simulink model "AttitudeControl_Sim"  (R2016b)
settings: Solver=ode4  StartTime=0.0  StopTime=30  FixedStep=0.001  RelTol=1e-3
InitFcn:
  | Init_control;
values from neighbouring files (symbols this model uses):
  DEG2RAD = 0.0174533    [Init_control.m]
  Kd_PITCH_AgngleRate = 0.001    [Init_control.m]
  Kd_ROLL_AgngleRate = 0.001    [Init_control.m]
  Kd_YAW_AngleRate = 0.00    (= 0)    [Init_control.m]
  Ki_PITCH_AgngleRate = 0.02    [Init_control.m]
  Ki_ROLL_AgngleRate = 0.02    [Init_control.m]
  Ki_YAW_AngleRate = 0.01    [Init_control.m]
  Kp_PITCH_AgngleRate = 0.1    [Init_control.m]
  Kp_PITCH_ANGLE = 6.5    [Init_control.m]
  Kp_ROLL_AgngleRate = 0.1    [Init_control.m]
  Kp_ROLL_ANGLE = 6.5    [Init_control.m]
  Kp_YAW_AngleRate = 0.3    [Init_control.m]
  MAX_CONTROL_ANGLE_PITCH = 35    [Init_control.m]
  MAX_CONTROL_ANGLE_RATE_PITCH = 220    [Init_control.m]
  MAX_CONTROL_ANGLE_RATE_ROLL = 220    [Init_control.m]
  MAX_CONTROL_ANGLE_RATE_Y = 200    [Init_control.m]
  MAX_CONTROL_ANGLE_ROLL = 35    [Init_control.m]
  Saturation_I_RP_Max = 0.3    [Init_control.m]
  Saturation_I_RP_Min = -0.3    [Init_control.m]
  Saturation_I_Y_Max = 0.2    [Init_control.m]
  Saturation_I_Y_Min = -0.2    [Init_control.m]
  THR_HOVER = 0.609    [Init_control.m]
undefined symbols (not defined in the file or in its folder): DiscIntNeverNeededParam, earthRadius, Receive, Send
libraries: simulink x5, aerolibfltsims x3, aerolib6dof2 x1
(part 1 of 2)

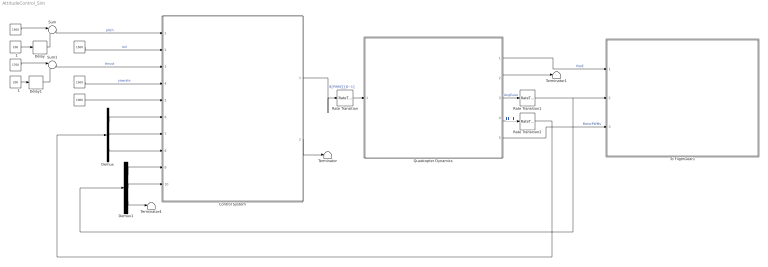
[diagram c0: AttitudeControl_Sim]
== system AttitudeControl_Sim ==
  " " : Constant  Value=1000  OutDataTypeStr=uint16
  "  " : Constant  Value=1500  OutDataTypeStr=uint16
  "   " : Constant  Value=1500  OutDataTypeStr=uint16
  "      " : Constant  Value=1700  OutDataTypeStr=uint16
  "          " : Constant  Value=1500  OutDataTypeStr=uint16
  "      1" : Constant  Value=200  OutDataTypeStr=uint16
  "  1" : Constant  Value=100  OutDataTypeStr=uint16
  Control System : Subsystem
  Delay : Delay  DelayLength=3000  InitialCondition=0  SampleTime=0.001
  Delay1 : Delay  DelayLength=1000  InitialCondition=0  SampleTime=0.001
  Demux : Demux  Outputs=3
  Demux1 : Demux  Outputs=3
  Quadcopter Dynamics : Subsystem
  Rate Transition : RateTransition  OutPortSampleTime=sampleRate
  Rate Transition1 : RateTransition  OutPortSampleTime=sampleRate
  Rate Transition2 : RateTransition  OutPortSampleTime=sampleRate
  Sum : Sum  Inputs=|++
  Sum1 : Sum  Inputs=|+-
  Terminator : Terminator
  Terminator1 : Terminator
  Terminator4 : Terminator
  To FlightGear1 : Subsystem
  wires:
  Quadcopter Dynamics/1(PosE) -> To FlightGear1/1(PosE)  "PosE"
  Quadcopter Dynamics/5(MotorRPMS) -> To FlightGear1/3(MotorPWMs)  "MotorPWMs"
  Control System/2(LED) -> Terminator/1
  Quadcopter Dynamics/3(AngEuler) -> Rate Transition1/1  "AngEular"
  Quadcopter Dynamics/4(AngRateB) -> Rate Transition2/1  "转动角速度"
  Demux/1 -> Control System/6(p)
  Demux/2 -> Control System/7(q)
  Demux/3 -> Control System/8(r)
  Demux1/1 -> Control System/9(roll)
  Demux1/2 -> Control System/10(pitch)
  Demux1/3 -> Terminator4/1
  "  "/1 -> Sum/1
  "  1"/1 -> Delay/1
  Delay/1 -> Sum/2
  Control System/1(PWM) -> Rate Transition/1  "8维PWM信号（0~1）"
  Quadcopter Dynamics/2(VelE) -> Terminator1/1
  Rate Transition/1 -> Quadcopter Dynamics/1(inPWMs)
  Rate Transition1/1 -> Demux1/1, To FlightGear1/2(AngEular)
  Rate Transition2/1 -> Demux/1
  "      "/1 -> Sum1/1
  "      1"/1 -> Delay1/1
  Delay1/1 -> Sum1/2
  Sum/1 -> Control System/1(ch1)  "pitch"
  "   "/1 -> Control System/2(ch2)  "roll"
  Sum1/1 -> Control System/3(ch3)  "thrust"
  "          "/1 -> Control System/4(ch4)  "yawrate"
  " "/1 -> Control System/5(ch5)

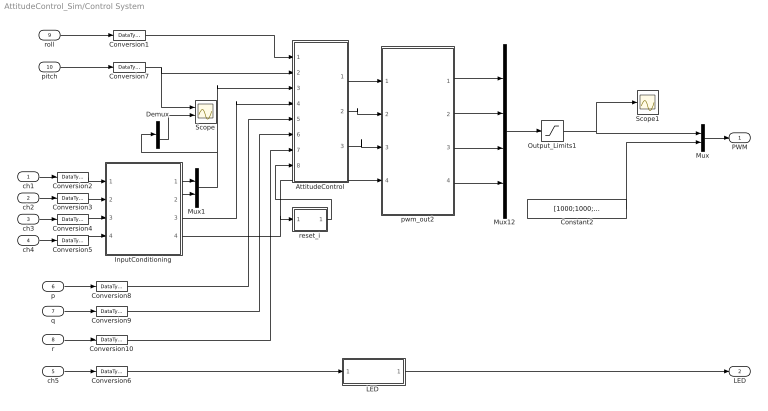
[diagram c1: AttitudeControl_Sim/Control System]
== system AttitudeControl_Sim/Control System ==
  ch1 : Inport  OutDataTypeStr=uint16  PortDimensions=1
  ch2 : Inport  Port=2  OutDataTypeStr=uint16  PortDimensions=1
  ch3 : Inport  Port=3  OutDataTypeStr=uint16  PortDimensions=1
  ch4 : Inport  Port=4  OutDataTypeStr=uint16  PortDimensions=1
  ch5 : Inport  Port=5  OutDataTypeStr=uint16  PortDimensions=1  Interpolate=off
  p : Inport  Port=6  PortDimensions=1
  q : Inport  Port=7  PortDimensions=1
  r : Inport  Port=8  PortDimensions=1
  roll : Inport  Port=9  PortDimensions=1
  pitch : Inport  Port=10  PortDimensions=1
  AttitudeControl : Subsystem
  Constant2 : Constant  Value=[1000;1000;1000;1000]
  Conversion{1..10} (10 alike) : DataTypeConversion  OutDataTypeStr=double
  Demux : Demux  Outputs=2
  InputConditioning : Subsystem
  "LED " : Subsystem
  Mux : Mux  Inputs=2
  Mux1 : Mux  Inputs=2
  Mux12 : Mux
  Output_Limits1 : Saturate  UpperLimit=2000  LowerLimit=1000
  Scope : Scope  NumInputPorts=2
  Scope1 : Scope
  pwm_out2 : MATLAB Function  SystemSampleTime=0.004
  reset_i : Subsystem
  PWM : Outport  PortDimensions=8
  LED : Outport  Port=2  PortDimensions=1
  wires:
  Mux12/1 -> Output_Limits1/1
  AttitudeControl/2(torque_pitch) -> pwm_out2/2(Pitch)
  AttitudeControl/1(torque_roll) -> pwm_out2/1(Roll)
  ch3/1 -> Conversion4/1
  pwm_out2/1(M1) -> Mux12/1
  ch5/1 -> Conversion6/1
  pwm_out2/3(M3) -> Mux12/3
  pwm_out2/2(M2) -> Mux12/2
  r/1 -> Conversion10/1
  AttitudeControl/3(torque_yaw) -> pwm_out2/3(Yaw)
  Mux1/1 -> AttitudeControl/3(roll_pitch_d), Demux/1
  q/1 -> Conversion9/1
  InputConditioning/3(yawRate_d) -> AttitudeControl/4(yawRate_d)
  p/1 -> Conversion8/1
  ch4/1 -> Conversion5/1
  pwm_out2/4(M4) -> Mux12/4
  "LED "/1(Out1) -> LED/1
  Conversion6/1 -> "LED "/1(In1)
  Conversion5/1 -> InputConditioning/4(ch4)
  Conversion4/1 -> InputConditioning/3(ch3)
  pitch/1 -> Conversion7/1
  Demux/2 -> Scope/2
  roll/1 -> Conversion1/1
  Constant2/1 -> Mux/2
  Output_Limits1/1 -> Scope1/1, Mux/1
  Mux/1 -> PWM/1
  ch1/1 -> Conversion2/1
  ch2/1 -> Conversion3/1
  Conversion2/1 -> InputConditioning/1(ch1)
  Conversion3/1 -> InputConditioning/2(ch2)
  InputConditioning/1(Roll_d) -> Mux1/1
  InputConditioning/2(Pitch_d) -> Mux1/2
  Conversion1/1 -> AttitudeControl/1(phi)
  Conversion7/1 -> AttitudeControl/2(theta), Scope/1
  Conversion8/1 -> AttitudeControl/5(p)
  Conversion9/1 -> AttitudeControl/6(q)
  Conversion10/1 -> AttitudeControl/7(r)
  reset_i/1(Out1) -> AttitudeControl/8(reset_i)
  InputConditioning/4(Thrust) -> pwm_out2/4(Thrust), reset_i/1(In1)

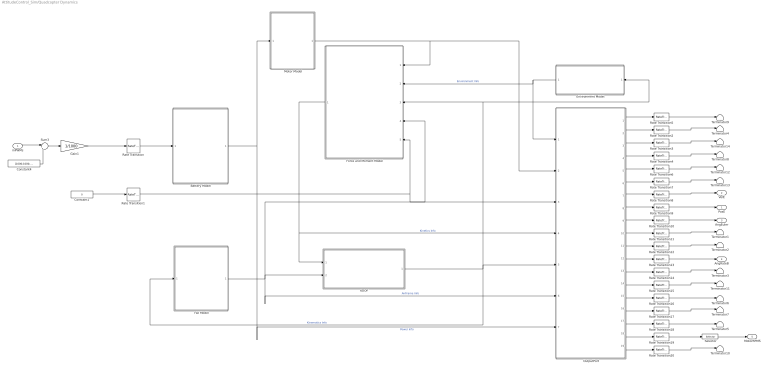
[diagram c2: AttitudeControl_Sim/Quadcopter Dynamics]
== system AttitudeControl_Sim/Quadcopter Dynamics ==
  inPWMs : Inport  PortDimensions=8
  6DOF : Subsystem
  Battery Model : Subsystem
  Constant1 : Constant  Value=0
  Constant4 : Constant  Value=[1000;1000;1000;1000;1000;1000;1000;1000]
  Environment Model : Subsystem
  Fail Model : Subsystem
  Force and Moment Model : Subsystem
  Gain1 : Gain  Gain=1/1000
  Motor Model : Subsystem
  OutputPort : Subsystem
  Rate Transition{,1..20} (21 alike) : RateTransition  OutPortSampleTime=ModelParam_BusSampleRate
  Selector : Selector  InputPortWidth=8  IndexOptions=Index vector (dialog)  Indices=[1 2 3 4]  OutputSizes=1
  Sum3 : Sum  Inputs=|+-
  Terminator{1..14} (14 alike) : Terminator
  PosE : Outport
  VelE : Outport  Port=2
  AngEuler : Outport  Port=3
  AngRateB : Outport  Port=4
  MotorRPMS : Outport  Port=5
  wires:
  Selector/1 -> MotorRPMS/1
  Constant4/1 -> Sum3/2
  inPWMs/1 -> Sum3/1
  Constant1/1 -> Rate Transition1/1
  Sum3/1 -> Gain1/1
  Rate Transition5/1 -> Terminator9/1
  Rate Transition2/1 -> Terminator4/1
  Rate Transition3/1 -> Terminator14/1
  Rate Transition4/1 -> Terminator8/1
  Rate Transition6/1 -> Terminator12/1
  Rate Transition7/1 -> Terminator13/1
  Rate Transition8/1 -> VelE/1
  Rate Transition9/1 -> PosE/1
  Rate Transition10/1 -> AngEuler/1
  Rate Transition11/1 -> Terminator1/1
  Rate Transition12/1 -> Terminator2/1
  Rate Transition13/1 -> AngRateB/1
  Rate Transition14/1 -> Terminator3/1
  Rate Transition15/1 -> Terminator11/1
  Rate Transition16/1 -> Terminator6/1
  Rate Transition17/1 -> Terminator7/1
  Rate Transition18/1 -> Terminator5/1
  Rate Transition19/1 -> Selector/1
  Rate Transition20/1 -> Terminator10/1
  Gain1/1 -> Rate Transition/1
  OutputPort/2(MavLinkStateQuatData) -> Rate Transition2/1
  Motor Model/1(MotorRads) -> OutputPort/2(MotorRads), Force and Moment Model/1(MotorRads)
  OutputPort/15(landed) -> Rate Transition16/1
  OutputPort/3(MavLinkGPSData) -> Rate Transition3/1
  OutputPort/1(MavLinkSensorData) -> Rate Transition5/1
  OutputPort/14(FailInfo) -> Rate Transition15/1
  OutputPort/13(AccB) -> Rate Transition14/1
  OutputPort/12(RateB) -> Rate Transition13/1
  OutputPort/11(PosGPS) -> Rate Transition12/1
  OutputPort/10(AngQuatern) -> Rate Transition11/1
  OutputPort/9(AngEuler) -> Rate Transition10/1
  OutputPort/8(PosE) -> Rate Transition9/1
  OutputPort/7(VelE) -> Rate Transition8/1
  OutputPort/6(SysTime) -> Rate Transition7/1
  OutputPort/5(MagDec) -> Rate Transition6/1
  OutputPort/4(HILGPS) -> Rate Transition4/1
  Battery Model/1(Battery Model Bus) -> OutputPort/7(Battery Model Bus), Motor Model/1(Battery Model Bus)  "Power Info"
  Fail Model/1(Fail Model Bus) -> OutputPort/6(Fail Model Bus), Force and Moment Model/4(Fail Model Bus), 6DOF/2(Fail Model Bus)  "AirFrame Info"
  Force and Moment Model/1(Force and Moment Model Bus) -> OutputPort/4(Force and Moment Model Bus), 6DOF/1(Force and Moment Model Bus)  "Kinetics Info"
  6DOF/1(6DOF Bus) -> OutputPort/5(6DOF Bus), Fail Model/1(6DOF Bus), Environment Model/1(6DOF Bus), Force and Moment Model/3(6DOF Bus)  "Kinematics Info"
  Environment Model/1(Environment Model Bus) -> OutputPort/1(Environment Model Bus), Force and Moment Model/2(Environment Model Bus)  "Environment Info"
  OutputPort/16(BattCellVoltage) -> Rate Transition17/1
  OutputPort/17(BattRemCapacity) -> Rate Transition18/1
  OutputPort/19(wind) -> Rate Transition20/1
  OutputPort/18(MotorRPMS) -> Rate Transition19/1
  Rate Transition/1 -> Battery Model/1(PWMin)
  Rate Transition1/1 -> OutputPort/3(zt), Force and Moment Model/5("tZ ")

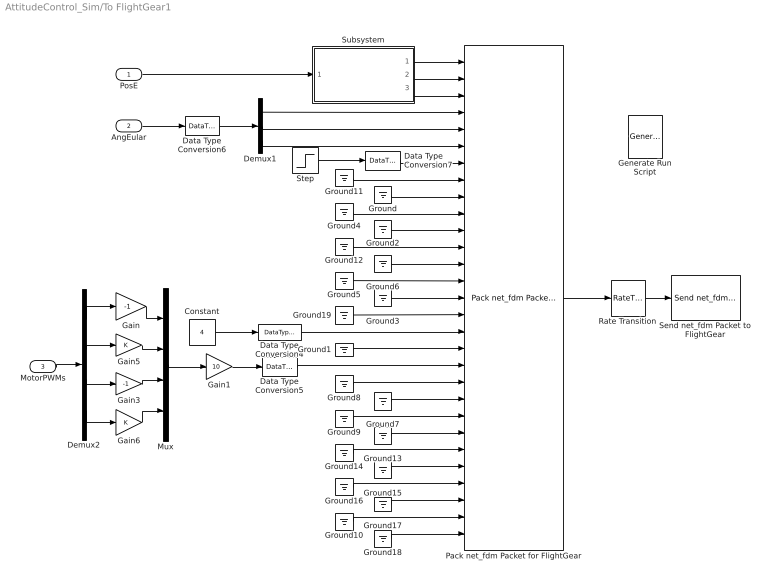
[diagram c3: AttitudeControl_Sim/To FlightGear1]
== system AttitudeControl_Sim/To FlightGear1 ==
  PosE : Inport
  AngEular : Inport  Port=2
  MotorPWMs : Inport  Port=3
  Constant : Constant  Value=4
  Data Type Conversion4 : DataTypeConversion  OutDataTypeStr=uint32
  Data Type Conversion5 : DataTypeConversion  OutDataTypeStr=single
  Data Type Conversion6 : DataTypeConversion  OutDataTypeStr=single
  Data Type Conversion7 : DataTypeConversion  OutDataTypeStr=single
  Demux1 : Demux  Outputs=3
  Demux2 : Demux
  Gain : Gain  Gain=-1
  Gain1 : Gain  Gain=10
  Gain3 : Gain  Gain=-1
  Gain5 : Gain
  Gain6 : Gain
  Generate Run Script : aerolibfltsims/Generate Run Script  OutputFileName=runfg_myownUAV.bat  FlightGearBaseDirectory=C:\Program Files\FlightGear 2016.1.2  GeometryModelName=myownUAV  DestinationPort=5502  OriginAddress=127.0.0.1  OriginPort=5505  LocalAddress=127.0.0.1  AirportId=KSFO  RunwayId=10L  InitialAltitude=0  InitialHeading=0  OffsetDistance=0  OffsetAzimuth=0  GenerateFile=off  Architecture=Default  dataFlow=Send-Receive
  Ground{,1..19} (20 alike) : Ground
  Mux : Mux
  Pack net_fdm Packet for FlightGear : aerolibfltsims/Pack net_fdm Packet for FlightGear  FlightGearVersion=v2016.1  ShowPositionAttitudeInputs=on  ShowVelocityAccelerationInputs=off  ShowControlSurfacePositionInputs=on  ShowEngineFuelInputs=on  ShowLandingGearInputs=off  ShowEnvironmentInputs=off  SampleTime=0.01
  Rate Transition : RateTransition
  Send net_fdm Packet to FlightGear : aerolibfltsims/Send net_fdm Packet to FlightGear  DestinationIpAddress=127.0.0.1  DestinationPort=5502  LocalIpPort=-1  varLen=off  SampleTime=0.005
  Step : Step  Time=0  SampleTime=0
  Subsystem : Subsystem
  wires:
  Pack net_fdm Packet for FlightGear/1 -> Rate Transition/1
  Data Type Conversion7/1 -> Pack net_fdm Packet for FlightGear/7
  Ground8/1 -> Pack net_fdm Packet for FlightGear/20
  Ground/1 -> Pack net_fdm Packet for FlightGear/9
  Ground7/1 -> Pack net_fdm Packet for FlightGear/21
  Ground9/1 -> Pack net_fdm Packet for FlightGear/22
  Ground13/1 -> Pack net_fdm Packet for FlightGear/23
  Ground14/1 -> Pack net_fdm Packet for FlightGear/24
  Ground15/1 -> Pack net_fdm Packet for FlightGear/25
  Ground16/1 -> Pack net_fdm Packet for FlightGear/26
  Ground17/1 -> Pack net_fdm Packet for FlightGear/27
  Ground10/1 -> Pack net_fdm Packet for FlightGear/28
  Ground18/1 -> Pack net_fdm Packet for FlightGear/29
  Step/1 -> Data Type Conversion7/1
  Data Type Conversion4/1 -> Pack net_fdm Packet for FlightGear/17
  Ground1/1 -> Pack net_fdm Packet for FlightGear/18
  Ground3/1 -> Pack net_fdm Packet for FlightGear/15
  Ground5/1 -> Pack net_fdm Packet for FlightGear/14
  Ground6/1 -> Pack net_fdm Packet for FlightGear/13
  Ground4/1 -> Pack net_fdm Packet for FlightGear/10
  Ground11/1 -> Pack net_fdm Packet for FlightGear/8
  Constant/1 -> Data Type Conversion4/1
  Data Type Conversion5/1 -> Pack net_fdm Packet for FlightGear/19
  Ground2/1 -> Pack net_fdm Packet for FlightGear/11
  Ground12/1 -> Pack net_fdm Packet for FlightGear/12
  AngEular/1 -> Data Type Conversion6/1
  MotorPWMs/1 -> Demux2/1
  Mux/1 -> Gain1/1
  Demux2/1 -> Gain/1
  Demux2/3 -> Gain3/1
  Gain/1 -> Mux/1
  Gain3/1 -> Mux/3
  Demux2/2 -> Gain5/1
  Gain5/1 -> Mux/2
  Demux2/4 -> Gain6/1
  Gain6/1 -> Mux/4
  Rate Transition/1 -> Send net_fdm Packet to FlightGear/1
  PosE/1 -> Subsystem/1(In1)
  Subsystem/1("l ") -> Pack net_fdm Packet for FlightGear/1
  Subsystem/2(u) -> Pack net_fdm Packet for FlightGear/2
  Subsystem/3(h) -> Pack net_fdm Packet for FlightGear/3
  Ground19/1 -> Pack net_fdm Packet for FlightGear/16
  Demux1/1 -> Pack net_fdm Packet for FlightGear/4
  Demux1/2 -> Pack net_fdm Packet for FlightGear/5
  Demux1/3 -> Pack net_fdm Packet for FlightGear/6
  Data Type Conversion6/1 -> Demux1/1
  Gain1/1 -> Data Type Conversion5/1

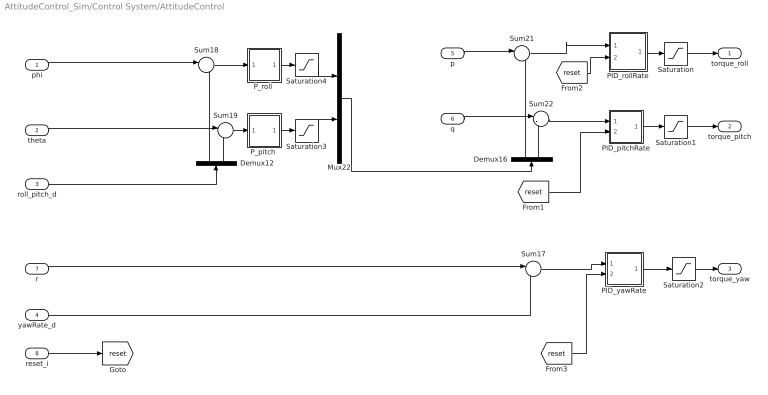
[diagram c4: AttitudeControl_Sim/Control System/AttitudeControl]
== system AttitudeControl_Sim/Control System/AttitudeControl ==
  phi : Inport
  theta : Inport  Port=2
  roll_pitch_d : Inport  Port=3
  yawRate_d : Inport  Port=4
  p : Inport  Port=5
  q : Inport  Port=6
  r : Inport  Port=7
  reset_i : Inport  Port=8
  Demux12 : Demux  Outputs=2
  Demux16 : Demux  Outputs=2
  Mux22 : Mux  Inputs=2
  PID_pitchRate : Subsystem
  PID_rollRate : Subsystem
  PID_yawRate : Subsystem
  "P_pitch " : Subsystem
  "P_roll " : Subsystem
  Saturation : Saturate  UpperLimit=1  LowerLimit=-1
  Saturation1 : Saturate  UpperLimit=1  LowerLimit=-1
  Saturation2 : Saturate
  Saturation3 : Saturate  UpperLimit=MAX_CONTROL_ANGLE_RATE_PITCH  LowerLimit=-MAX_CONTROL_ANGLE_RATE_PITCH
  Saturation4 : Saturate  UpperLimit=MAX_CONTROL_ANGLE_RATE_ROLL  LowerLimit=-MAX_CONTROL_ANGLE_RATE_ROLL
  Sum{17..19,21..22} (5 alike) : Sum  Inputs=|-+
  torque_roll : Outport
  torque_pitch : Outport  Port=2
  torque_yaw : Outport  Port=3
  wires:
  r/1 -> Sum17/1
  Sum19/1 -> "P_pitch "/1(x)
  "P_pitch "/1(y) -> Saturation3/1
  "P_roll "/1(y) -> Saturation4/1
  roll_pitch_d/1 -> Demux12/1
  Demux12/1 -> Sum18/2
  Demux12/2 -> Sum19/2
  phi/1 -> Sum18/1
  theta/1 -> Sum19/1
  Sum18/1 -> "P_roll "/1(x)
  Sum22/1 -> PID_pitchRate/1(x)
  Sum17/1 -> PID_yawRate/1(x)
  p/1 -> Sum21/1
  q/1 -> Sum22/1
  Sum21/1 -> PID_rollRate/1(x)
  Demux16/1 -> Sum21/2
  PID_pitchRate/1(y) -> Saturation1/1
  PID_rollRate/1(y) -> Saturation/1
  PID_yawRate/1(y) -> Saturation2/1
  yawRate_d/1 -> Sum17/2
  reset_i/1 -> [reset]
  [reset] -> PID_rollRate/2(reset_i)
  [reset] -> PID_pitchRate/2(reset_i)
  [reset] -> PID_yawRate/2(reset_i)
  Saturation/1 -> torque_roll/1
  Saturation1/1 -> torque_pitch/1
  Saturation2/1 -> torque_yaw/1
  Mux22/1 -> Demux16/1
  Saturation4/1 -> Mux22/1
  Saturation3/1 -> Mux22/2
  Demux16/2 -> Sum22/2

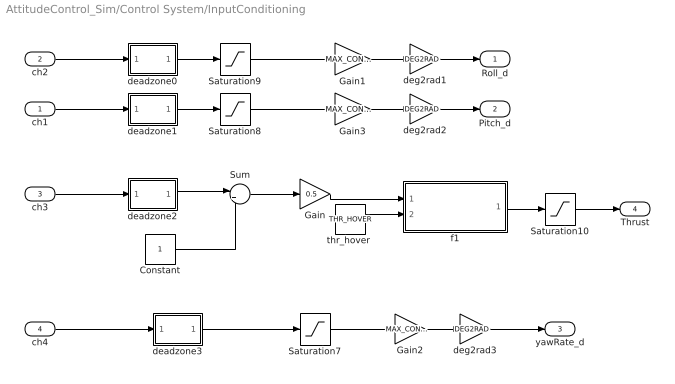
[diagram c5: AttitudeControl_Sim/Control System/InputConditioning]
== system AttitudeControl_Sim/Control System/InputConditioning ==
  ch1 : Inport
  ch2 : Inport  Port=2
  ch3 : Inport  Port=3
  ch4 : Inport  Port=4
  Constant : Constant
  Gain : Gain  Gain=0.5
  Gain1 : Gain  Gain=MAX_CONTROL_ANGLE_ROLL  OutDataTypeStr=Inherit: Inherit via back propagation
  Gain2 : Gain  Gain=MAX_CONTROL_ANGLE_RATE_Y
  Gain3 : Gain  Gain=MAX_CONTROL_ANGLE_PITCH  OutDataTypeStr=Inherit: Inherit via back propagation
  Saturation10 : Saturate  UpperLimit=1  LowerLimit=0
  Saturation7 : Saturate  UpperLimit=1  LowerLimit=-1
  Saturation8 : Saturate  UpperLimit=1  LowerLimit=-1
  Saturation9 : Saturate  UpperLimit=1  LowerLimit=-1
  Sum : Sum  Inputs=|++
  deadzone0 : MATLAB Function  TreatAsAtomicUnit=on
  deadzone1 : MATLAB Function  TreatAsAtomicUnit=on
  deadzone2 : MATLAB Function  TreatAsAtomicUnit=on
  deadzone3 : MATLAB Function  TreatAsAtomicUnit=on
  deg2rad1 : Gain  Gain=DEG2RAD
  deg2rad2 : Gain  Gain=DEG2RAD
  deg2rad3 : Gain  Gain=DEG2RAD
  f1 : MATLAB Function  TreatAsAtomicUnit=on
  "thr_hover " : Constant  Value=THR_HOVER
  Roll_d : Outport
  Pitch_d : Outport  Port=2
  yawRate_d : Outport  Port=3
  Thrust : Outport  Port=4
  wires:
  deadzone2/1(y) -> Sum/1
  ch3/1 -> deadzone2/1(u)
  deadzone1/1(y) -> Saturation8/1
  Saturation10/1 -> Thrust/1
  deadzone0/1(y) -> Saturation9/1
  ch2/1 -> deadzone0/1(u)
  ch1/1 -> deadzone1/1(u)
  Saturation9/1 -> Gain1/1
  Saturation8/1 -> Gain3/1
  Gain3/1 -> deg2rad2/1
  Constant/1 -> Sum/2
  Sum/1 -> Gain/1
  Gain1/1 -> deg2rad1/1
  deg2rad1/1 -> Roll_d/1
  deg2rad2/1 -> Pitch_d/1
  Saturation7/1 -> Gain2/1
  deadzone3/1(y) -> Saturation7/1
  ch4/1 -> deadzone3/1(u)
  Gain2/1 -> deg2rad3/1
  deg2rad3/1 -> yawRate_d/1
  "thr_hover "/1 -> f1/2(hover)
  Gain/1 -> f1/1(in)
  f1/1(y) -> Saturation10/1

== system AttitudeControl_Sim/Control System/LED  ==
  In1 : Inport
  Compare To Constant3 : simulink/Logic and Bit Operations/Compare To Constant  relop=>=  const=uint16(1500)  OutDataTypeStr=boolean
  Out1 : Outport
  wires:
  Compare To Constant3/1 -> Out1/1
  In1/1 -> Compare To Constant3/1

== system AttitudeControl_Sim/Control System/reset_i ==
  In1 : Inport
  Compare To Constant3 : simulink/Logic and Bit Operations/Compare To Constant  relop=<=  const=0.2  OutDataTypeStr=boolean
  Out1 : Outport
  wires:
  In1/1 -> Compare To Constant3/1
  Compare To Constant3/1 -> Out1/1

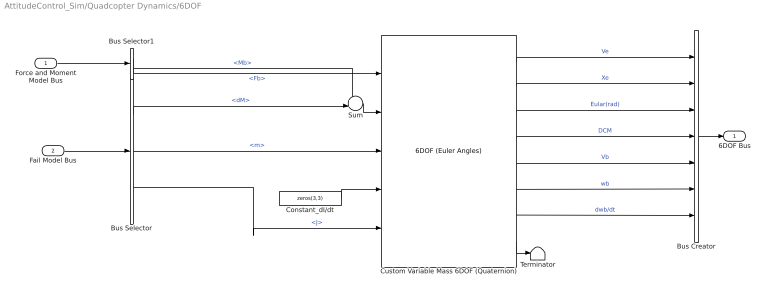
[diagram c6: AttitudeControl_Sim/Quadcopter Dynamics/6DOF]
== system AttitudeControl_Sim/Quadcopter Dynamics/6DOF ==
  Force and Moment Model Bus : Inport
  Fail Model Bus : Inport  Port=2
  Bus Creator : BusCreator  Inputs=7
  Bus Selector : BusSelector  OutputSignals=dM,m,J
  Bus Selector1 : BusSelector  OutputSignals=Fb,Mb
  Constant_dI/dt : Constant  Value=zeros(3,3)
  Custom Variable Mass 6DOF (Quaternion) : aerolib6dof2/6DOF (Euler Angles)  units=Metric (MKS)  mtype=Custom Variable  rep=Quaternion  xme_0=ModelInit_PosE  Vm_0=ModelInit_VelB  eul_0=ModelInit_AngEuler  pm_0=ModelInit_RateB  mass_0=1.0  mass_e=0.5  mass_f=2.0  inertia=eye(3)  inertia_e=eye(3)  inertia_f=2*eye(3)  k_quat=1.0  vre_flag=off
  Sum : Sum  Inputs=++|
  Terminator : Terminator
  6DOF Bus : Outport
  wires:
  Bus Selector1/1 -> Custom Variable Mass 6DOF (Quaternion)/1  "<Fb>"
  Bus Selector/2 -> Custom Variable Mass 6DOF (Quaternion)/3  "<m>"
  Custom Variable Mass 6DOF (Quaternion)/8 -> Terminator/1
  Sum/1 -> Custom Variable Mass 6DOF (Quaternion)/2
  Constant_dI/dt/1 -> Custom Variable Mass 6DOF (Quaternion)/4
  Custom Variable Mass 6DOF (Quaternion)/5 -> Bus Creator/5  "Vb"
  Custom Variable Mass 6DOF (Quaternion)/6 -> Bus Creator/6  "wb"
  Custom Variable Mass 6DOF (Quaternion)/1 -> Bus Creator/1  "Ve"
  Custom Variable Mass 6DOF (Quaternion)/4 -> Bus Creator/4  "DCM"
  Custom Variable Mass 6DOF (Quaternion)/2 -> Bus Creator/2  "Xe"
  Custom Variable Mass 6DOF (Quaternion)/3 -> Bus Creator/3  "Eular(rad)"
  Custom Variable Mass 6DOF (Quaternion)/7 -> Bus Creator/7  "dwb/dt"
  Bus Selector/3 -> Custom Variable Mass 6DOF (Quaternion)/5  "<J>"
  Bus Selector/1 -> Sum/2  "<dM>"
  Bus Selector1/2 -> Sum/1  "<Mb>"
  Fail Model Bus/1 -> Bus Selector/1
  Force and Moment Model Bus/1 -> Bus Selector1/1
  Bus Creator/1 -> 6DOF Bus/1

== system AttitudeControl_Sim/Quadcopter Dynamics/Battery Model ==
  PWMin : Inport
  Battery Model_sfcn : S-Function  FunctionName=Battery_sf  SFunctionModules=""  SFunctionDeploymentMode=off  EnableBusSupport=off
  __InputSSForSFun__ : Subsystem
  __OutputSSForSFun__ : Subsystem
  Battery Model Bus : Outport
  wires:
  PWMin/1 -> __InputSSForSFun__/1(PWMin)
  __InputSSForSFun__/1(__UniqueOutportName__1__) -> Battery Model_sfcn/1
  Battery Model_sfcn/1 -> __OutputSSForSFun__/1(__UniqueInportName__1__)
  Battery Model_sfcn/2 -> __OutputSSForSFun__/2(__UniqueInportName__2__)
  Battery Model_sfcn/3 -> __OutputSSForSFun__/3(__UniqueInportName__3__)
  __OutputSSForSFun__/1(Battery Model Bus) -> Battery Model Bus/1

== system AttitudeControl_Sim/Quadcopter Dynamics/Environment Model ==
  6DOF Bus : Inport
  Environment Model_sfcn : S-Function  FunctionName=Environment_sf  Parameters=sfcnParam1, sfcnParam2, sfcnParam3  SFunctionModules=""  SFunctionDeploymentMode=off  EnableBusSupport=off  SFcnStateName=DWORK0
  __InputSSForSFun__ : Subsystem
  __OutputSSForSFun__ : Subsystem
  Environment Model Bus : Outport
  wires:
  6DOF Bus/1 -> __InputSSForSFun__/1(6DOF Bus)
  __InputSSForSFun__/1(__UniqueOutportName__1__) -> Environment Model_sfcn/1
  __InputSSForSFun__/2(__UniqueOutportName__2__) -> Environment Model_sfcn/2
  __InputSSForSFun__/3(__UniqueOutportName__3__) -> Environment Model_sfcn/3
  __InputSSForSFun__/4(__UniqueOutportName__4__) -> Environment Model_sfcn/4
  __InputSSForSFun__/5(__UniqueOutportName__5__) -> Environment Model_sfcn/5
  __InputSSForSFun__/6(__UniqueOutportName__6__) -> Environment Model_sfcn/6
  __InputSSForSFun__/7(__UniqueOutportName__7__) -> Environment Model_sfcn/7
  Environment Model_sfcn/1 -> __OutputSSForSFun__/1(__UniqueInportName__1__)
  Environment Model_sfcn/2 -> __OutputSSForSFun__/2(__UniqueInportName__2__)
  Environment Model_sfcn/3 -> __OutputSSForSFun__/3(__UniqueInportName__3__)
  Environment Model_sfcn/4 -> __OutputSSForSFun__/4(__UniqueInportName__4__)
  Environment Model_sfcn/5 -> __OutputSSForSFun__/5(__UniqueInportName__5__)
  Environment Model_sfcn/6 -> __OutputSSForSFun__/6(__UniqueInportName__6__)
  Environment Model_sfcn/7 -> __OutputSSForSFun__/7(__UniqueInportName__7__)
  __OutputSSForSFun__/1(Environment Model Bus) -> Environment Model Bus/1

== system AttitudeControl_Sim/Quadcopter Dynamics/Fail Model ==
  6DOF Bus : Inport
  Fail Model_sfcn : S-Function  FunctionName=Fail_sf  Parameters=sfcnParam1, sfcnParam2, sfcnParam3  SFunctionModules=""  SFunctionDeploymentMode=off  EnableBusSupport=off
  __InputSSForSFun__ : Subsystem
  __OutputSSForSFun__ : Subsystem
  Fail Model Bus : Outport
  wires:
  6DOF Bus/1 -> __InputSSForSFun__/1(6DOF Bus)
  __InputSSForSFun__/1(__UniqueOutportName__1__) -> Fail Model_sfcn/1
  __InputSSForSFun__/2(__UniqueOutportName__2__) -> Fail Model_sfcn/2
  __InputSSForSFun__/3(__UniqueOutportName__3__) -> Fail Model_sfcn/3
  __InputSSForSFun__/4(__UniqueOutportName__4__) -> Fail Model_sfcn/4
  __InputSSForSFun__/5(__UniqueOutportName__5__) -> Fail Model_sfcn/5
  __InputSSForSFun__/6(__UniqueOutportName__6__) -> Fail Model_sfcn/6
  __InputSSForSFun__/7(__UniqueOutportName__7__) -> Fail Model_sfcn/7
  Fail Model_sfcn/1 -> __OutputSSForSFun__/1(__UniqueInportName__1__)
  Fail Model_sfcn/2 -> __OutputSSForSFun__/2(__UniqueInportName__2__)
  Fail Model_sfcn/3 -> __OutputSSForSFun__/3(__UniqueInportName__3__)
  __OutputSSForSFun__/1(Fail Model Bus) -> Fail Model Bus/1

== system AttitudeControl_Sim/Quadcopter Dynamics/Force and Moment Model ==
  MotorRads : Inport
  Environment Model Bus : Inport  Port=2
  6DOF Bus : Inport  Port=3
  Fail Model Bus : Inport  Port=4
  "tZ " : Inport  Port=5
  Force and Moment Model_sfcn : S-Function  FunctionName=Force_sf  Parameters=sfcnParam1, sfcnParam2, sfcnParam3, sfcnParam4, sfcnParam5, sfcnParam6, sfcnParam7, sfcnParam8  SFunctionModules=""  SFunctionDeploymentMode=off  EnableBusSupport=off
  __InputSSForSFun__ : Subsystem
  __OutputSSForSFun__ : Subsystem
  Force and Moment Model Bus : Outport
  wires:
  MotorRads/1 -> __InputSSForSFun__/1(MotorRads)
  Environment Model Bus/1 -> __InputSSForSFun__/2(Environment Model Bus)
  6DOF Bus/1 -> __InputSSForSFun__/3(6DOF Bus)
  Fail Model Bus/1 -> __InputSSForSFun__/4(Fail Model Bus)
  "tZ "/1 -> __InputSSForSFun__/5("tZ ")
  __InputSSForSFun__/1(__UniqueOutportName__1__) -> Force and Moment Model_sfcn/1
  __InputSSForSFun__/2(__UniqueOutportName__2__) -> Force and Moment Model_sfcn/2
  __InputSSForSFun__/3(__UniqueOutportName__3__) -> Force and Moment Model_sfcn/3
  __InputSSForSFun__/4(__UniqueOutportName__4__) -> Force and Moment Model_sfcn/4
  __InputSSForSFun__/5(__UniqueOutportName__5__) -> Force and Moment Model_sfcn/5
  __InputSSForSFun__/6(__UniqueOutportName__6__) -> Force and Moment Model_sfcn/6
  __InputSSForSFun__/7(__UniqueOutportName__7__) -> Force and Moment Model_sfcn/7
  __InputSSForSFun__/8(__UniqueOutportName__8__) -> Force and Moment Model_sfcn/8
  __InputSSForSFun__/9(__UniqueOutportName__9__) -> Force and Moment Model_sfcn/9
  __InputSSForSFun__/10(__UniqueOutportName__10__) -> Force and Moment Model_sfcn/10
  __InputSSForSFun__/11(__UniqueOutportName__11__) -> Force and Moment Model_sfcn/11
  __InputSSForSFun__/12(__UniqueOutportName__12__) -> Force and Moment Model_sfcn/12
  __InputSSForSFun__/13(__UniqueOutportName__13__) -> Force and Moment Model_sfcn/13
  __InputSSForSFun__/14(__UniqueOutportName__14__) -> Force and Moment Model_sfcn/14
  __InputSSForSFun__/15(__UniqueOutportName__15__) -> Force and Moment Model_sfcn/15
  __InputSSForSFun__/16(__UniqueOutportName__16__) -> Force and Moment Model_sfcn/16
  __InputSSForSFun__/17(__UniqueOutportName__17__) -> Force and Moment Model_sfcn/17
  __InputSSForSFun__/18(__UniqueOutportName__18__) -> Force and Moment Model_sfcn/18
  __InputSSForSFun__/19(__UniqueOutportName__19__) -> Force and Moment Model_sfcn/19
  Force and Moment Model_sfcn/1 -> __OutputSSForSFun__/1(__UniqueInportName__1__)
  Force and Moment Model_sfcn/2 -> __OutputSSForSFun__/2(__UniqueInportName__2__)
  Force and Moment Model_sfcn/3 -> __OutputSSForSFun__/3(__UniqueInportName__3__)
  __OutputSSForSFun__/1(Force and Moment Model Bus) -> Force and Moment Model Bus/1

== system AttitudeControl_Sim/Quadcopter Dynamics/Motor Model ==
  Battery Model Bus : Inport
  Motor Model_sfcn : S-Function  FunctionName=Motor_sf  Parameters=sfcnParam1, sfcnParam2, sfcnParam3, sfcnParam4, sfcnParam5  SFunctionModules=""  SFunctionDeploymentMode=off  EnableBusSupport=off
  __InputSSForSFun__ : Subsystem
  __OutputSSForSFun__ : Subsystem
  MotorRads : Outport
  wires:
  Battery Model Bus/1 -> __InputSSForSFun__/1(Battery Model Bus)
  __InputSSForSFun__/1(__UniqueOutportName__1__) -> Motor Model_sfcn/1
  __InputSSForSFun__/2(__UniqueOutportName__2__) -> Motor Model_sfcn/2
  __InputSSForSFun__/3(__UniqueOutportName__3__) -> Motor Model_sfcn/3
  Motor Model_sfcn/1 -> __OutputSSForSFun__/1(__UniqueInportName__1__)
  __OutputSSForSFun__/1(MotorRads) -> MotorRads/1

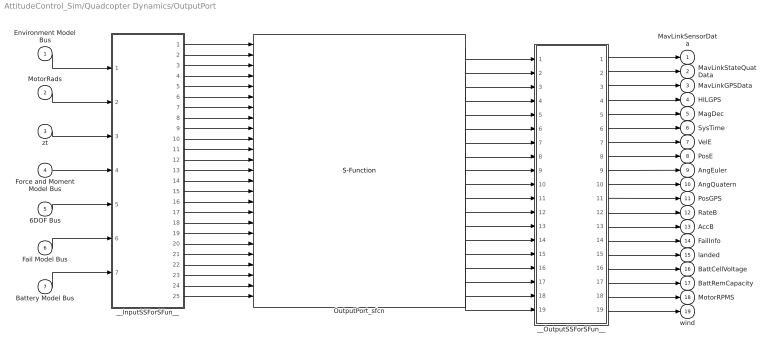
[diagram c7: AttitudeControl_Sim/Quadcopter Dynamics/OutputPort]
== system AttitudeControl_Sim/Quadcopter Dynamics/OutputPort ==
  Environment Model Bus : Inport
  MotorRads : Inport  Port=2
  zt : Inport  Port=3
  Force and Moment Model Bus : Inport  Port=4
  6DOF Bus : Inport  Port=5
  Fail Model Bus : Inport  Port=6
  Battery Model Bus : Inport  Port=7
  OutputPort_sfcn : S-Function  FunctionName=OutputPort_sf  Parameters=sfcnParam1, sfcnParam2, sfcnParam3  SFunctionModules=""  SFunctionDeploymentMode=off  EnableBusSupport=off  SFcnStateName=DWORK0
  __InputSSForSFun__ : Subsystem
  __OutputSSForSFun__ : Subsystem
  MavLinkSensorData : Outport  OutDataTypeStr=Bus: MavLinkSensor  SampleTime=[-1 0]
  MavLinkStateQuatData : Outport  Port=2  OutDataTypeStr=Bus: MavLinkStateQuat  SampleTime=[-1 0]
  MavLinkGPSData : Outport  Port=3  OutDataTypeStr=Bus: MavLinkGPS  SampleTime=[-1 0]
  HILGPS : Outport  Port=4  OutDataTypeStr=Bus: HILGPS  SampleTime=[-1 0]
  MagDec : Outport  Port=5
  SysTime : Outport  Port=6
  VelE : Outport  Port=7
  PosE : Outport  Port=8
  AngEuler : Outport  Port=9
  AngQuatern : Outport  Port=10
  PosGPS : Outport  Port=11
  RateB : Outport  Port=12
  AccB : Outport  Port=13
  FailInfo : Outport  Port=14
  landed : Outport  Port=15
  BattCellVoltage : Outport  Port=16
  BattRemCapacity : Outport  Port=17
  MotorRPMS : Outport  Port=18
  wind : Outport  Port=19
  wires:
  Environment Model Bus/1 -> __InputSSForSFun__/1(Environment Model Bus)
  MotorRads/1 -> __InputSSForSFun__/2(MotorRads)
  zt/1 -> __InputSSForSFun__/3(zt)
  Force and Moment Model Bus/1 -> __InputSSForSFun__/4(Force and Moment Model Bus)
  6DOF Bus/1 -> __InputSSForSFun__/5(6DOF Bus)
  Fail Model Bus/1 -> __InputSSForSFun__/6(Fail Model Bus)
  Battery Model Bus/1 -> __InputSSForSFun__/7(Battery Model Bus)
  __InputSSForSFun__/1(__UniqueOutportName__1__) -> OutputPort_sfcn/1
  __InputSSForSFun__/2(__UniqueOutportName__2__) -> OutputPort_sfcn/2
  __InputSSForSFun__/3(__UniqueOutportName__3__) -> OutputPort_sfcn/3
  __InputSSForSFun__/4(__UniqueOutportName__4__) -> OutputPort_sfcn/4
  __InputSSForSFun__/5(__UniqueOutportName__5__) -> OutputPort_sfcn/5
  __InputSSForSFun__/6(__UniqueOutportName__6__) -> OutputPort_sfcn/6
  __InputSSForSFun__/7(__UniqueOutportName__7__) -> OutputPort_sfcn/7
  __InputSSForSFun__/8(__UniqueOutportName__8__) -> OutputPort_sfcn/8
  __InputSSForSFun__/9(__UniqueOutportName__9__) -> OutputPort_sfcn/9
  __InputSSForSFun__/10(__UniqueOutportName__10__) -> OutputPort_sfcn/10
  __InputSSForSFun__/11(__UniqueOutportName__11__) -> OutputPort_sfcn/11
  __InputSSForSFun__/12(__UniqueOutportName__12__) -> OutputPort_sfcn/12
  __InputSSForSFun__/13(__UniqueOutportName__13__) -> OutputPort_sfcn/13
  __InputSSForSFun__/14(__UniqueOutportName__14__) -> OutputPort_sfcn/14
  __InputSSForSFun__/15(__UniqueOutportName__15__) -> OutputPort_sfcn/15
  __InputSSForSFun__/16(__UniqueOutportName__16__) -> OutputPort_sfcn/16
  __InputSSForSFun__/17(__UniqueOutportName__17__) -> OutputPort_sfcn/17
  __InputSSForSFun__/18(__UniqueOutportName__18__) -> OutputPort_sfcn/18
  __InputSSForSFun__/19(__UniqueOutportName__19__) -> OutputPort_sfcn/19
  __InputSSForSFun__/20(__UniqueOutportName__20__) -> OutputPort_sfcn/20
  __InputSSForSFun__/21(__UniqueOutportName__21__) -> OutputPort_sfcn/21
  __InputSSForSFun__/22(__UniqueOutportName__22__) -> OutputPort_sfcn/22
  __InputSSForSFun__/23(__UniqueOutportName__23__) -> OutputPort_sfcn/23
  __InputSSForSFun__/24(__UniqueOutportName__24__) -> OutputPort_sfcn/24
  __InputSSForSFun__/25(__UniqueOutportName__25__) -> OutputPort_sfcn/25
  OutputPort_sfcn/1 -> __OutputSSForSFun__/1(__UniqueInportName__1__)
  OutputPort_sfcn/2 -> __OutputSSForSFun__/2(__UniqueInportName__2__)
  OutputPort_sfcn/3 -> __OutputSSForSFun__/3(__UniqueInportName__3__)
  OutputPort_sfcn/4 -> __OutputSSForSFun__/4(__UniqueInportName__4__)
  OutputPort_sfcn/5 -> __OutputSSForSFun__/5(__UniqueInportName__5__)
  OutputPort_sfcn/6 -> __OutputSSForSFun__/6(__UniqueInportName__6__)
  OutputPort_sfcn/7 -> __OutputSSForSFun__/7(__UniqueInportName__7__)
  OutputPort_sfcn/8 -> __OutputSSForSFun__/8(__UniqueInportName__8__)
  OutputPort_sfcn/9 -> __OutputSSForSFun__/9(__UniqueInportName__9__)
  OutputPort_sfcn/10 -> __OutputSSForSFun__/10(__UniqueInportName__10__)
  OutputPort_sfcn/11 -> __OutputSSForSFun__/11(__UniqueInportName__11__)
  OutputPort_sfcn/12 -> __OutputSSForSFun__/12(__UniqueInportName__12__)
  OutputPort_sfcn/13 -> __OutputSSForSFun__/13(__UniqueInportName__13__)
  OutputPort_sfcn/14 -> __OutputSSForSFun__/14(__UniqueInportName__14__)
  OutputPort_sfcn/15 -> __OutputSSForSFun__/15(__UniqueInportName__15__)
  OutputPort_sfcn/16 -> __OutputSSForSFun__/16(__UniqueInportName__16__)
  OutputPort_sfcn/17 -> __OutputSSForSFun__/17(__UniqueInportName__17__)
  OutputPort_sfcn/18 -> __OutputSSForSFun__/18(__UniqueInportName__18__)
  OutputPort_sfcn/19 -> __OutputSSForSFun__/19(__UniqueInportName__19__)
  __OutputSSForSFun__/1(MavLinkSensorData) -> MavLinkSensorData/1
  __OutputSSForSFun__/2(MavLinkStateQuatData) -> MavLinkStateQuatData/1
  __OutputSSForSFun__/3(MavLinkGPSData) -> MavLinkGPSData/1
  __OutputSSForSFun__/4(HILGPS) -> HILGPS/1
  __OutputSSForSFun__/5(MagDec) -> MagDec/1
  __OutputSSForSFun__/6(SysTime) -> SysTime/1
  __OutputSSForSFun__/7(VelE) -> VelE/1
  __OutputSSForSFun__/8(PosE) -> PosE/1
  __OutputSSForSFun__/9(AngEuler) -> AngEuler/1
  __OutputSSForSFun__/10(AngQuatern) -> AngQuatern/1
  __OutputSSForSFun__/11(PosGPS) -> PosGPS/1
  __OutputSSForSFun__/12(RateB) -> RateB/1
  __OutputSSForSFun__/13(AccB) -> AccB/1
  __OutputSSForSFun__/14(FailInfo) -> FailInfo/1
  __OutputSSForSFun__/15(landed) -> landed/1
  __OutputSSForSFun__/16(BattCellVoltage) -> BattCellVoltage/1
  __OutputSSForSFun__/17(BattRemCapacity) -> BattRemCapacity/1
  __OutputSSForSFun__/18(MotorRPMS) -> MotorRPMS/1
  __OutputSSForSFun__/19(wind) -> wind/1

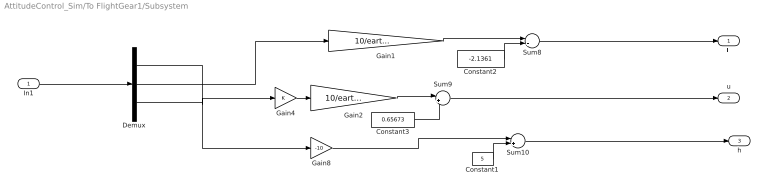
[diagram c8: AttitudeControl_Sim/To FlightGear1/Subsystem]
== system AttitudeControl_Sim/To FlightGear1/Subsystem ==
  In1 : Inport
  Constant1 : Constant  Value=5  VectorParams1D=off
  Constant2 : Constant  Value=-2.1361  VectorParams1D=off
  Constant3 : Constant  Value=0.65673  VectorParams1D=off
  Demux : Demux  Outputs=3
  Gain1 : Gain  Gain=10/earthRadius
  Gain2 : Gain  Gain=10/earthRadius
  Gain4 : Gain
  Gain8 : Gain  Gain=-10
  Sum10 : Sum  Inputs=|++
  Sum8 : Sum  Inputs=|++
  Sum9 : Sum  Inputs=|++
  "l " : Outport
  u : Outport  Port=2
  h : Outport  Port=3
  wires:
  Constant3/1 -> Sum9/2
  Constant1/1 -> Sum10/2
  Demux/1 -> Gain4/1
  Demux/3 -> Gain8/1
  Constant2/1 -> Sum8/2
  Gain2/1 -> Sum9/1
  Gain1/1 -> Sum8/1
  Gain8/1 -> Sum10/1
  Demux/2 -> Gain1/1
  Gain4/1 -> Gain2/1
  Sum10/1 -> h/1
  Sum9/1 -> u/1
  In1/1 -> Demux/1
  Sum8/1 -> "l "/1

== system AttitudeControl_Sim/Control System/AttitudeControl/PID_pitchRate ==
  x : Inport
  reset_i : Inport  Port=2
  Derivative Gain : Gain  DisableCoverage=on  Gain=Kd_PITCH_AgngleRate  ParamMin=-100  ParamMax=100  OutMin=-100  OutMax=100
  Discrete Derivative : simulink/Discrete/Discrete Derivative  gainval=1.0  ICPrevScaledInput=0.0  OutMin=[]  OutMax=[]  OutDataType=fixdt(1, 16)  OutScaling=2^-10  DoSatur=off
  Discrete-Time Integrator : DiscreteIntegrator  ExternalReset=either  InitialConditionSetting=State (most efficient)  SampleTime=-1  LimitOutput=on  UpperSaturationLimit=Saturation_I_RP_Max  LowerSaturationLimit=Saturation_I_RP_Min  ICPrevOutput=DiscIntNeverNeededParam  ICPrevScaledInput=DiscIntNeverNeededParam
  Gain : Gain  Gain=Kp_PITCH_AgngleRate
  Integral Gain : Gain  DisableCoverage=on  Gain=Ki_PITCH_AgngleRate
  Sum : Sum  Inputs=+++
  y : Outport  InitialOutput=0
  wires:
  Discrete-Time Integrator/1 -> Sum/2
  Discrete Derivative/1 -> Sum/3
  Sum/1 -> y/1
  Gain/1 -> Sum/1
  Derivative Gain/1 -> Discrete Derivative/1
  Integral Gain/1 -> Discrete-Time Integrator/1
  x/1 -> Derivative Gain/1, Integral Gain/1, Gain/1
  reset_i/1 -> Discrete-Time Integrator/2

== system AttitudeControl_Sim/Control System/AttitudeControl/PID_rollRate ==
  x : Inport
  reset_i : Inport  Port=2
  Derivative Gain : Gain  DisableCoverage=on  Gain=Kd_ROLL_AgngleRate  ParamMin=-100  ParamMax=100  OutMin=-100  OutMax=100
  Discrete Derivative : simulink/Discrete/Discrete Derivative  gainval=1.0  ICPrevScaledInput=0.0  OutMin=[]  OutMax=[]  OutDataType=fixdt(1, 16)  OutScaling=2^-10  DoSatur=off
  Discrete-Time Integrator : DiscreteIntegrator  ExternalReset=either  InitialConditionSetting=State (most efficient)  SampleTime=-1  LimitOutput=on  UpperSaturationLimit=Saturation_I_RP_Max  LowerSaturationLimit=Saturation_I_RP_Min  ICPrevOutput=DiscIntNeverNeededParam  ICPrevScaledInput=DiscIntNeverNeededParam
  Gain : Gain  Gain=Kp_ROLL_AgngleRate
  Integral Gain : Gain  DisableCoverage=on  Gain=Ki_ROLL_AgngleRate
  Sum : Sum  Inputs=+++
  y : Outport  InitialOutput=0
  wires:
  x/1 -> Gain/1, Integral Gain/1, Derivative Gain/1
  Integral Gain/1 -> Discrete-Time Integrator/1
  Derivative Gain/1 -> Discrete Derivative/1
  Gain/1 -> Sum/1
  Sum/1 -> y/1
  Discrete Derivative/1 -> Sum/3
  Discrete-Time Integrator/1 -> Sum/2
  reset_i/1 -> Discrete-Time Integrator/2

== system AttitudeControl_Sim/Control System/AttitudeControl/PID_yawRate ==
  x : Inport
  reset_i : Inport  Port=2
  Derivative Gain : Gain  DisableCoverage=on  Gain=Kd_YAW_AngleRate  ParamMin=-100  ParamMax=100  OutMin=-100  OutMax=100
  Discrete Derivative : simulink/Discrete/Discrete Derivative  gainval=1.0  ICPrevScaledInput=0.0  OutMin=[]  OutMax=[]  OutDataType=fixdt(1, 16)  OutScaling=2^-10  DoSatur=off
  Discrete-Time Integrator : DiscreteIntegrator  ExternalReset=either  InitialConditionSetting=State (most efficient)  SampleTime=-1  LimitOutput=on  UpperSaturationLimit=Saturation_I_Y_Max  LowerSaturationLimit=Saturation_I_Y_Min  ICPrevOutput=DiscIntNeverNeededParam  ICPrevScaledInput=DiscIntNeverNeededParam
  Gain : Gain  Gain=Kp_YAW_AngleRate
  Integral Gain : Gain  DisableCoverage=on  Gain=Ki_YAW_AngleRate
  Sum : Sum  Inputs=+++
  y : Outport  InitialOutput=0
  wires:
  x/1 -> Gain/1, Integral Gain/1, Derivative Gain/1
  Integral Gain/1 -> Discrete-Time Integrator/1
  Derivative Gain/1 -> Discrete Derivative/1
  Gain/1 -> Sum/1
  Sum/1 -> y/1
  Discrete Derivative/1 -> Sum/3
  Discrete-Time Integrator/1 -> Sum/2
  reset_i/1 -> Discrete-Time Integrator/2

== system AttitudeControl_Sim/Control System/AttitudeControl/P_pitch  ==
  x : Inport
  Gain : Gain  Gain=Kp_PITCH_ANGLE
  y : Outport  InitialOutput=0
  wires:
  x/1 -> Gain/1
  Gain/1 -> y/1

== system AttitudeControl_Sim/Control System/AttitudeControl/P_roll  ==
  x : Inport
  Gain : Gain  Gain=Kp_ROLL_ANGLE
  y : Outport  InitialOutput=0
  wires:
  Gain/1 -> y/1
  x/1 -> Gain/1

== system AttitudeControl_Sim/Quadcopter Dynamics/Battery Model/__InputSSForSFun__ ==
  PWMin : Inport
  __UniqueOutportName__1__ : Outport
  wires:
  PWMin/1 -> __UniqueOutportName__1__/1

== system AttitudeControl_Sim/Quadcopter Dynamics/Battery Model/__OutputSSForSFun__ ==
  __UniqueInportName__1__ : Inport
  __UniqueInportName__2__ : Inport  Port=2
  __UniqueInportName__3__ : Inport  Port=3
  Mux1 : BusCreator  Inputs=3
  Battery Model Bus : Outport
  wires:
  __UniqueInportName__1__/1 -> Mux1/1  "PWMOut"
  __UniqueInportName__2__/1 -> Mux1/2  "cellVol"
  __UniqueInportName__3__/1 -> Mux1/3  "remCapa"
  Mux1/1 -> Battery Model Bus/1

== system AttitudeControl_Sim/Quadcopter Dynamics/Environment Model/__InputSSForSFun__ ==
  6DOF Bus : Inport
  temporaryBusSelectName_1 : BusSelector  OutputSignals=Ve,Xe,Eular(rad),DCM,Vb,wb,dwb/dt
  __UniqueOutportName__1__ : Outport
  __UniqueOutportName__2__ : Outport  Port=2
  __UniqueOutportName__3__ : Outport  Port=3
  __UniqueOutportName__4__ : Outport  Port=4
  __UniqueOutportName__5__ : Outport  Port=5
  __UniqueOutportName__6__ : Outport  Port=6
  __UniqueOutportName__7__ : Outport  Port=7
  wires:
  6DOF Bus/1 -> temporaryBusSelectName_1/1
  temporaryBusSelectName_1/1 -> __UniqueOutportName__1__/1  "<Ve>"
  temporaryBusSelectName_1/2 -> __UniqueOutportName__2__/1  "<Xe>"
  temporaryBusSelectName_1/3 -> __UniqueOutportName__3__/1  "<Eular(rad)>"
  temporaryBusSelectName_1/4 -> __UniqueOutportName__4__/1  "<DCM>"
  temporaryBusSelectName_1/5 -> __UniqueOutportName__5__/1  "<Vb>"
  temporaryBusSelectName_1/6 -> __UniqueOutportName__6__/1  "<wb>"
  temporaryBusSelectName_1/7 -> __UniqueOutportName__7__/1  "<dwb/dt>"

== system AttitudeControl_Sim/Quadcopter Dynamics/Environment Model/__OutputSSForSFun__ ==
  __UniqueInportName__1__ : Inport
  __UniqueInportName__2__ : Inport  Port=2
  __UniqueInportName__3__ : Inport  Port=3
  __UniqueInportName__4__ : Inport  Port=4
  __UniqueInportName__5__ : Inport  Port=5
  __UniqueInportName__6__ : Inport  Port=6
  __UniqueInportName__7__ : Inport  Port=7
  Mux1 : BusCreator  Inputs=7
  Environment Model Bus : Outport
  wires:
  __UniqueInportName__1__/1 -> Mux1/1  "PosGPS"
  __UniqueInportName__2__/1 -> Mux1/2  "gravity"
  __UniqueInportName__3__/1 -> Mux1/3  "TempC"
  __UniqueInportName__4__/1 -> Mux1/4  "AirPressure"
  __UniqueInportName__5__/1 -> Mux1/5  "Rho"
  __UniqueInportName__6__/1 -> Mux1/6  "Windb"
  __UniqueInportName__7__/1 -> Mux1/7  "Wind"
  Mux1/1 -> Environment Model Bus/1

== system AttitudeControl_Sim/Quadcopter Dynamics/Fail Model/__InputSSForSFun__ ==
  6DOF Bus : Inport
  temporaryBusSelectName_1 : BusSelector  OutputSignals=Ve,Xe,Eular(rad),DCM,Vb,wb,dwb/dt
  __UniqueOutportName__1__ : Outport
  __UniqueOutportName__2__ : Outport  Port=2
  __UniqueOutportName__3__ : Outport  Port=3
  __UniqueOutportName__4__ : Outport  Port=4
  __UniqueOutportName__5__ : Outport  Port=5
  __UniqueOutportName__6__ : Outport  Port=6
  __UniqueOutportName__7__ : Outport  Port=7
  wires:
  6DOF Bus/1 -> temporaryBusSelectName_1/1
  temporaryBusSelectName_1/1 -> __UniqueOutportName__1__/1  "<Ve>"
  temporaryBusSelectName_1/2 -> __UniqueOutportName__2__/1  "<Xe>"
  temporaryBusSelectName_1/3 -> __UniqueOutportName__3__/1  "<Eular(rad)>"
  temporaryBusSelectName_1/4 -> __UniqueOutportName__4__/1  "<DCM>"
  temporaryBusSelectName_1/5 -> __UniqueOutportName__5__/1  "<Vb>"
  temporaryBusSelectName_1/6 -> __UniqueOutportName__6__/1  "<wb>"
  temporaryBusSelectName_1/7 -> __UniqueOutportName__7__/1  "<dwb/dt>"

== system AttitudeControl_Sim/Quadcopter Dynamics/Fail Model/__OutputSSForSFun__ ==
  __UniqueInportName__1__ : Inport
  __UniqueInportName__2__ : Inport  Port=2
  __UniqueInportName__3__ : Inport  Port=3
  Mux1 : BusCreator  Inputs=3
  Fail Model Bus : Outport
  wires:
  __UniqueInportName__1__/1 -> Mux1/1  "m"
  __UniqueInportName__2__/1 -> Mux1/2  "J"
  __UniqueInportName__3__/1 -> Mux1/3  "dM"
  Mux1/1 -> Fail Model Bus/1

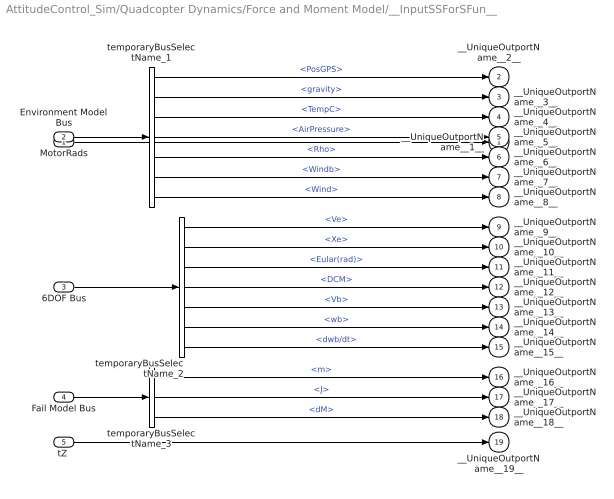
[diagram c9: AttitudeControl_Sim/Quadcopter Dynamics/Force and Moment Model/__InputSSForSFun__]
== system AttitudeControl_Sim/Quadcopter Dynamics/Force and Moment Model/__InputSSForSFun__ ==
  MotorRads : Inport
  Environment Model Bus : Inport  Port=2
  6DOF Bus : Inport  Port=3
  Fail Model Bus : Inport  Port=4
  "tZ " : Inport  Port=5
  temporaryBusSelectName_1 : BusSelector  OutputSignals=PosGPS,gravity,TempC,AirPressure,Rho,Windb,Wind
  temporaryBusSelectName_2 : BusSelector  OutputSignals=Ve,Xe,Eular(rad),DCM,Vb,wb,dwb/dt
  temporaryBusSelectName_3 : BusSelector  OutputSignals=m,J,dM
  __UniqueOutportName__1__ : Outport
  __UniqueOutportName__2__ : Outport  Port=2
  __UniqueOutportName__3__ : Outport  Port=3
  __UniqueOutportName__4__ : Outport  Port=4
  __UniqueOutportName__5__ : Outport  Port=5
  __UniqueOutportName__6__ : Outport  Port=6
  __UniqueOutportName__7__ : Outport  Port=7
  __UniqueOutportName__8__ : Outport  Port=8
  __UniqueOutportName__9__ : Outport  Port=9
  __UniqueOutportName__10__ : Outport  Port=10
  __UniqueOutportName__11__ : Outport  Port=11
  __UniqueOutportName__12__ : Outport  Port=12
  __UniqueOutportName__13__ : Outport  Port=13
  __UniqueOutportName__14__ : Outport  Port=14
  __UniqueOutportName__15__ : Outport  Port=15
  __UniqueOutportName__16__ : Outport  Port=16
  __UniqueOutportName__17__ : Outport  Port=17
  __UniqueOutportName__18__ : Outport  Port=18
  __UniqueOutportName__19__ : Outport  Port=19
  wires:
  Environment Model Bus/1 -> temporaryBusSelectName_1/1
  6DOF Bus/1 -> temporaryBusSelectName_2/1
  Fail Model Bus/1 -> temporaryBusSelectName_3/1
  MotorRads/1 -> __UniqueOutportName__1__/1
  temporaryBusSelectName_1/1 -> __UniqueOutportName__2__/1  "<PosGPS>"
  temporaryBusSelectName_1/2 -> __UniqueOutportName__3__/1  "<gravity>"
  temporaryBusSelectName_1/3 -> __UniqueOutportName__4__/1  "<TempC>"
  temporaryBusSelectName_1/4 -> __UniqueOutportName__5__/1  "<AirPressure>"
  temporaryBusSelectName_1/5 -> __UniqueOutportName__6__/1  "<Rho>"
  temporaryBusSelectName_1/6 -> __UniqueOutportName__7__/1  "<Windb>"
  temporaryBusSelectName_1/7 -> __UniqueOutportName__8__/1  "<Wind>"
  temporaryBusSelectName_2/1 -> __UniqueOutportName__9__/1  "<Ve>"
  temporaryBusSelectName_2/2 -> __UniqueOutportName__10__/1  "<Xe>"
  temporaryBusSelectName_2/3 -> __UniqueOutportName__11__/1  "<Eular(rad)>"
  temporaryBusSelectName_2/4 -> __UniqueOutportName__12__/1  "<DCM>"
  temporaryBusSelectName_2/5 -> __UniqueOutportName__13__/1  "<Vb>"
  temporaryBusSelectName_2/6 -> __UniqueOutportName__14__/1  "<wb>"
  temporaryBusSelectName_2/7 -> __UniqueOutportName__15__/1  "<dwb/dt>"
  temporaryBusSelectName_3/1 -> __UniqueOutportName__16__/1  "<m>"
  temporaryBusSelectName_3/2 -> __UniqueOutportName__17__/1  "<J>"
  temporaryBusSelectName_3/3 -> __UniqueOutportName__18__/1  "<dM>"
  "tZ "/1 -> __UniqueOutportName__19__/1

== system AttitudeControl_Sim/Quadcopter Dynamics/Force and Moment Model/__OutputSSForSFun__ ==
  __UniqueInportName__1__ : Inport
  __UniqueInportName__2__ : Inport  Port=2
  __UniqueInportName__3__ : Inport  Port=3
  Mux1 : BusCreator  Inputs=3
  Force and Moment Model Bus : Outport
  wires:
  __UniqueInportName__1__/1 -> Mux1/1  "Fb"
  __UniqueInportName__2__/1 -> Mux1/2  "Mb"
  __UniqueInportName__3__/1 -> Mux1/3  "landed"
  Mux1/1 -> Force and Moment Model Bus/1

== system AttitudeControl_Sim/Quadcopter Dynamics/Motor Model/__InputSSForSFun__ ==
  Battery Model Bus : Inport
  temporaryBusSelectName_1 : BusSelector  OutputSignals=PWMOut,cellVol,remCapa
  __UniqueOutportName__1__ : Outport
  __UniqueOutportName__2__ : Outport  Port=2
  __UniqueOutportName__3__ : Outport  Port=3
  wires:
  Battery Model Bus/1 -> temporaryBusSelectName_1/1
  temporaryBusSelectName_1/1 -> __UniqueOutportName__1__/1  "<PWMOut>"
  temporaryBusSelectName_1/2 -> __UniqueOutportName__2__/1  "<cellVol>"
  temporaryBusSelectName_1/3 -> __UniqueOutportName__3__/1  "<remCapa>"

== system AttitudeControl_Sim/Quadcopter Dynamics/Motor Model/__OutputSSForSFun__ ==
  __UniqueInportName__1__ : Inport
  MotorRads : Outport
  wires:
  __UniqueInportName__1__/1 -> MotorRads/1  "y"

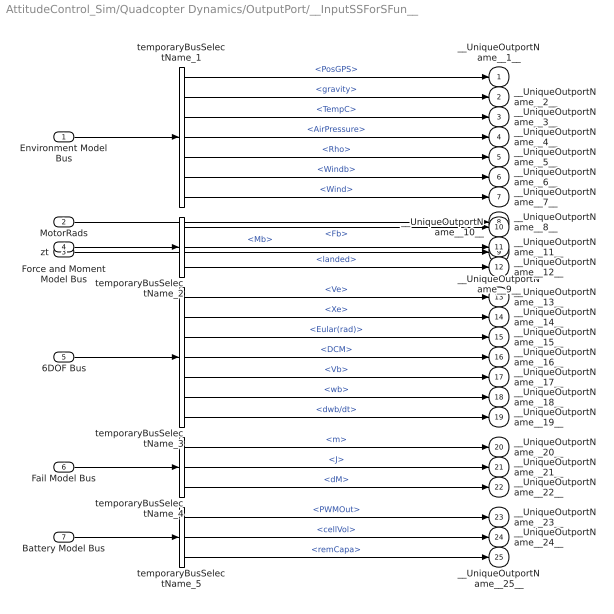
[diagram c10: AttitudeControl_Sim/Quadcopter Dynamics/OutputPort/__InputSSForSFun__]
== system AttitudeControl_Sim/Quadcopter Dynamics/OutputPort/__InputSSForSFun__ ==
  Environment Model Bus : Inport
  MotorRads : Inport  Port=2
  zt : Inport  Port=3
  Force and Moment Model Bus : Inport  Port=4
  6DOF Bus : Inport  Port=5
  Fail Model Bus : Inport  Port=6
  Battery Model Bus : Inport  Port=7
  temporaryBusSelectName_1 : BusSelector  OutputSignals=PosGPS,gravity,TempC,AirPressure,Rho,Windb,Wind
  temporaryBusSelectName_2 : BusSelector  OutputSignals=Fb,Mb,landed
  temporaryBusSelectName_3 : BusSelector  OutputSignals=Ve,Xe,Eular(rad),DCM,Vb,wb,dwb/dt
  temporaryBusSelectName_4 : BusSelector  OutputSignals=m,J,dM
  temporaryBusSelectName_5 : BusSelector  OutputSignals=PWMOut,cellVol,remCapa
  __UniqueOutportName__1__ : Outport
  __UniqueOutportName__2__ : Outport  Port=2
  __UniqueOutportName__3__ : Outport  Port=3
  __UniqueOutportName__4__ : Outport  Port=4
  __UniqueOutportName__5__ : Outport  Port=5
  __UniqueOutportName__6__ : Outport  Port=6
  __UniqueOutportName__7__ : Outport  Port=7
  __UniqueOutportName__8__ : Outport  Port=8
  __UniqueOutportName__9__ : Outport  Port=9
  __UniqueOutportName__10__ : Outport  Port=10
  __UniqueOutportName__11__ : Outport  Port=11
  __UniqueOutportName__12__ : Outport  Port=12
  __UniqueOutportName__13__ : Outport  Port=13
  __UniqueOutportName__14__ : Outport  Port=14
  __UniqueOutportName__15__ : Outport  Port=15
  __UniqueOutportName__16__ : Outport  Port=16
  __UniqueOutportName__17__ : Outport  Port=17
  __UniqueOutportName__18__ : Outport  Port=18
  __UniqueOutportName__19__ : Outport  Port=19
  __UniqueOutportName__20__ : Outport  Port=20
  __UniqueOutportName__21__ : Outport  Port=21
  __UniqueOutportName__22__ : Outport  Port=22
  __UniqueOutportName__23__ : Outport  Port=23
  __UniqueOutportName__24__ : Outport  Port=24
  __UniqueOutportName__25__ : Outport  Port=25
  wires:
  Environment Model Bus/1 -> temporaryBusSelectName_1/1
  Force and Moment Model Bus/1 -> temporaryBusSelectName_2/1
  6DOF Bus/1 -> temporaryBusSelectName_3/1
  Fail Model Bus/1 -> temporaryBusSelectName_4/1
  Battery Model Bus/1 -> temporaryBusSelectName_5/1
  temporaryBusSelectName_1/1 -> __UniqueOutportName__1__/1  "<PosGPS>"
  temporaryBusSelectName_1/2 -> __UniqueOutportName__2__/1  "<gravity>"
  temporaryBusSelectName_1/3 -> __UniqueOutportName__3__/1  "<TempC>"
  temporaryBusSelectName_1/4 -> __UniqueOutportName__4__/1  "<AirPressure>"
  temporaryBusSelectName_1/5 -> __UniqueOutportName__5__/1  "<Rho>"
  temporaryBusSelectName_1/6 -> __UniqueOutportName__6__/1  "<Windb>"
  temporaryBusSelectName_1/7 -> __UniqueOutportName__7__/1  "<Wind>"
  MotorRads/1 -> __UniqueOutportName__8__/1
  zt/1 -> __UniqueOutportName__9__/1
  temporaryBusSelectName_2/1 -> __UniqueOutportName__10__/1  "<Fb>"
  temporaryBusSelectName_2/2 -> __UniqueOutportName__11__/1  "<Mb>"
  temporaryBusSelectName_2/3 -> __UniqueOutportName__12__/1  "<landed>"
  temporaryBusSelectName_3/1 -> __UniqueOutportName__13__/1  "<Ve>"
  temporaryBusSelectName_3/2 -> __UniqueOutportName__14__/1  "<Xe>"
  temporaryBusSelectName_3/3 -> __UniqueOutportName__15__/1  "<Eular(rad)>"
  temporaryBusSelectName_3/4 -> __UniqueOutportName__16__/1  "<DCM>"
  temporaryBusSelectName_3/5 -> __UniqueOutportName__17__/1  "<Vb>"
  temporaryBusSelectName_3/6 -> __UniqueOutportName__18__/1  "<wb>"
  temporaryBusSelectName_3/7 -> __UniqueOutportName__19__/1  "<dwb/dt>"
  temporaryBusSelectName_4/1 -> __UniqueOutportName__20__/1  "<m>"
  temporaryBusSelectName_4/2 -> __UniqueOutportName__21__/1  "<J>"
  temporaryBusSelectName_4/3 -> __UniqueOutportName__22__/1  "<dM>"
  temporaryBusSelectName_5/1 -> __UniqueOutportName__23__/1  "<PWMOut>"
  temporaryBusSelectName_5/2 -> __UniqueOutportName__24__/1  "<cellVol>"
  temporaryBusSelectName_5/3 -> __UniqueOutportName__25__/1  "<remCapa>"
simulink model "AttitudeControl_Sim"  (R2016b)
settings: Solver=ode4  StartTime=0.0  StopTime=30  FixedStep=0.001  RelTol=1e-3
InitFcn:
  | Init_control;
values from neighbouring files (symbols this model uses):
  DEG2RAD = 0.0174533    [Init_control.m]
  Kd_PITCH_AgngleRate = 0.001    [Init_control.m]
  Kd_ROLL_AgngleRate = 0.001    [Init_control.m]
  Kd_YAW_AngleRate = 0.00    (= 0)    [Init_control.m]
  Ki_PITCH_AgngleRate = 0.02    [Init_control.m]
  Ki_ROLL_AgngleRate = 0.02    [Init_control.m]
  Ki_YAW_AngleRate = 0.01    [Init_control.m]
  Kp_PITCH_AgngleRate = 0.1    [Init_control.m]
  Kp_PITCH_ANGLE = 6.5    [Init_control.m]
  Kp_ROLL_AgngleRate = 0.1    [Init_control.m]
  Kp_ROLL_ANGLE = 6.5    [Init_control.m]
  Kp_YAW_AngleRate = 0.3    [Init_control.m]
  MAX_CONTROL_ANGLE_PITCH = 35    [Init_control.m]
  MAX_CONTROL_ANGLE_RATE_PITCH = 220    [Init_control.m]
  MAX_CONTROL_ANGLE_RATE_ROLL = 220    [Init_control.m]
  MAX_CONTROL_ANGLE_RATE_Y = 200    [Init_control.m]
  MAX_CONTROL_ANGLE_ROLL = 35    [Init_control.m]
  Saturation_I_RP_Max = 0.3    [Init_control.m]
  Saturation_I_RP_Min = -0.3    [Init_control.m]
  Saturation_I_Y_Max = 0.2    [Init_control.m]
  Saturation_I_Y_Min = -0.2    [Init_control.m]
  THR_HOVER = 0.609    [Init_control.m]
undefined symbols (not defined in the file or in its folder): DiscIntNeverNeededParam, earthRadius, Receive, Send
libraries: simulink x5, aerolibfltsims x3, aerolib6dof2 x1
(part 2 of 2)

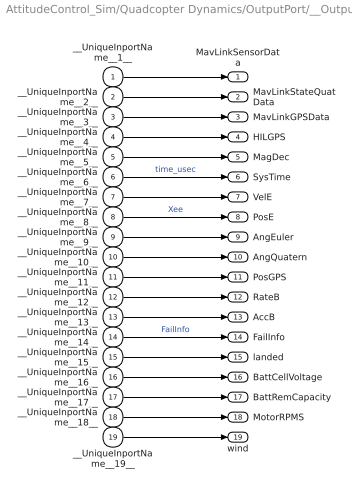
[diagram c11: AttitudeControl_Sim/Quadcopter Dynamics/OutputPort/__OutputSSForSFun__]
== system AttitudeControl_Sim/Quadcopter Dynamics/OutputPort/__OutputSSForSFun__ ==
  __UniqueInportName__1__ : Inport
  __UniqueInportName__2__ : Inport  Port=2
  __UniqueInportName__3__ : Inport  Port=3
  __UniqueInportName__4__ : Inport  Port=4
  __UniqueInportName__5__ : Inport  Port=5
  __UniqueInportName__6__ : Inport  Port=6
  __UniqueInportName__7__ : Inport  Port=7
  __UniqueInportName__8__ : Inport  Port=8
  __UniqueInportName__9__ : Inport  Port=9
  __UniqueInportName__10__ : Inport  Port=10
  __UniqueInportName__11__ : Inport  Port=11
  __UniqueInportName__12__ : Inport  Port=12
  __UniqueInportName__13__ : Inport  Port=13
  __UniqueInportName__14__ : Inport  Port=14
  __UniqueInportName__15__ : Inport  Port=15
  __UniqueInportName__16__ : Inport  Port=16
  __UniqueInportName__17__ : Inport  Port=17
  __UniqueInportName__18__ : Inport  Port=18
  __UniqueInportName__19__ : Inport  Port=19
  MavLinkSensorData : Outport  OutDataTypeStr=Bus: MavLinkSensor  SampleTime=[-1 0]
  MavLinkStateQuatData : Outport  Port=2  OutDataTypeStr=Bus: MavLinkStateQuat  SampleTime=[-1 0]
  MavLinkGPSData : Outport  Port=3  OutDataTypeStr=Bus: MavLinkGPS  SampleTime=[-1 0]
  HILGPS : Outport  Port=4  OutDataTypeStr=Bus: HILGPS  SampleTime=[-1 0]
  MagDec : Outport  Port=5
  SysTime : Outport  Port=6
  VelE : Outport  Port=7
  PosE : Outport  Port=8
  AngEuler : Outport  Port=9
  AngQuatern : Outport  Port=10
  PosGPS : Outport  Port=11
  RateB : Outport  Port=12
  AccB : Outport  Port=13
  FailInfo : Outport  Port=14
  landed : Outport  Port=15
  BattCellVoltage : Outport  Port=16
  BattRemCapacity : Outport  Port=17
  MotorRPMS : Outport  Port=18
  wind : Outport  Port=19
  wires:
  __UniqueInportName__1__/1 -> MavLinkSensorData/1
  __UniqueInportName__2__/1 -> MavLinkStateQuatData/1
  __UniqueInportName__3__/1 -> MavLinkGPSData/1
  __UniqueInportName__4__/1 -> HILGPS/1
  __UniqueInportName__5__/1 -> MagDec/1
  __UniqueInportName__6__/1 -> SysTime/1  "time_usec"
  __UniqueInportName__7__/1 -> VelE/1
  __UniqueInportName__8__/1 -> PosE/1  "Xee"
  __UniqueInportName__9__/1 -> AngEuler/1
  __UniqueInportName__10__/1 -> AngQuatern/1
  __UniqueInportName__11__/1 -> PosGPS/1
  __UniqueInportName__12__/1 -> RateB/1
  __UniqueInportName__13__/1 -> AccB/1
  __UniqueInportName__14__/1 -> FailInfo/1  "FailInfo"
  __UniqueInportName__15__/1 -> landed/1
  __UniqueInportName__16__/1 -> BattCellVoltage/1
  __UniqueInportName__17__/1 -> BattRemCapacity/1
  __UniqueInportName__18__/1 -> MotorRPMS/1
  __UniqueInportName__19__/1 -> wind/1

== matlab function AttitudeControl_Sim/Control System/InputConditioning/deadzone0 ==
function y = fcn(u)
%将遥控输入的范围控制在1100~1900，同时设置一个死区，死区大小为±deadZone
RCMin = 1100;
RCMax = 1900;
RCMid = (RCMin+RCMax)/2;
deadZoneRate = 0.05;
deadZone = deadZoneRate*(RCMax-RCMin);
k=1/(RCMax-RCMid-deadZone);
%限幅
if(u < RCMin)
    u = RCMin;
elseif(u > RCMax)
    u = RCMax;
end
%死区
 if(u > RCMid+deadZone)
    y = (u-RCMid-deadZone)*k;
 elseif(u < RCMid-deadZone)
     y = (u-RCMid+deadZone)*k;
 else
     y = 0;
 end

 end

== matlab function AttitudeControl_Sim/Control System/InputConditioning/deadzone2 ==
function y = fcn(u)
%将遥控输入的范围控制在1100~1900，同时设置一个死区，死区大小为±deadZone
RCMin = 1100;
RCMax = 1900;
RCMid = (RCMin+RCMax)/2;
deadZoneRate = 0.05;
deadZone = deadZoneRate*(RCMax-RCMin);
k=1/(RCMax-RCMid-deadZone);
%限幅
if(u < RCMin)
    u = RCMin;
elseif(u > RCMax)
    u = RCMax;
end
%死区
 if(u > RCMid+deadZone)
    y = (u-RCMid-deadZone)*k;
 elseif(u < RCMid-deadZone)
     y = (u-RCMid+deadZone)*k;
 else
     y = 0;
 end

 end

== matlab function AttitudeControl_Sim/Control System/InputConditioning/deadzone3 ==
function y = fcn(u)
%将遥控输入的范围控制在1100~1900，同时设置一个死区，死区大小为±deadZone
RCMin = 1100;
RCMax = 1900;
RCMid = (RCMin+RCMax)/2;
deadZoneRate = 0.05;
deadZone = deadZoneRate*(RCMax-RCMin);
k=1/(RCMax-RCMid-deadZone);
%限幅
if(u < RCMin)
    u = RCMin;
elseif(u > RCMax)
    u = RCMax;
end
%死区
 if(u > RCMid+deadZone)
    y = (u-RCMid-deadZone)*k;
 elseif(u < RCMid-deadZone)
     y = (u-RCMid+deadZone)*k;
 else
     y = 0;
 end

 end

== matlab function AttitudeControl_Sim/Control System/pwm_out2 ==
function [M1, M2, M3, M4] = motor_mixer(Roll, Pitch, Yaw, Thrust)
%quadrotorX
%3     1
%  \ /
%  / \
%2     4

idle_PWM = 1000;
scale = 1000;

M1 = (Thrust - Roll + Pitch + Yaw) * scale + idle_PWM;
M2 = (Thrust + Roll - Pitch + Yaw) * scale + idle_PWM;
M3 = (Thrust + Roll + Pitch - Yaw) * scale + idle_PWM;
M4 = (Thrust - Roll - Pitch - Yaw) * scale + idle_PWM;

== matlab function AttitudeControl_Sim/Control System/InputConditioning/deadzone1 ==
function y = fcn(u)
%将遥控输入的范围控制在1100~1900，同时设置一个死区，死区大小为±deadZone
RCMin = 1100;
RCMax = 1900;
RCMid = (RCMin+RCMax)/2;
deadZoneRate = 0.05;
deadZone = deadZoneRate*(RCMax-RCMin);
k=1/(RCMax-RCMid-deadZone);
%限幅
if(u < RCMin)
    u = RCMin;
elseif(u > RCMax)
    u = RCMax;
end
%死区
 if(u > RCMid+deadZone)
    y = (u-RCMid-deadZone)*k;
 elseif(u < RCMid-deadZone)
     y = (u-RCMid+deadZone)*k;
 else
     y = 0;
 end

 end

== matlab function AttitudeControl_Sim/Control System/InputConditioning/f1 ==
function y = thr_curve(in,hover)
%输入油门归一化后为0~1，中点为0.5
%经过这个函数，油门在中间位置时，输出为悬停油门 hover
if in < 0.5
	y=2 * in * hover;
else
	y=hover + 2 * (in - 0.5) * (1.0 - hover);
end
